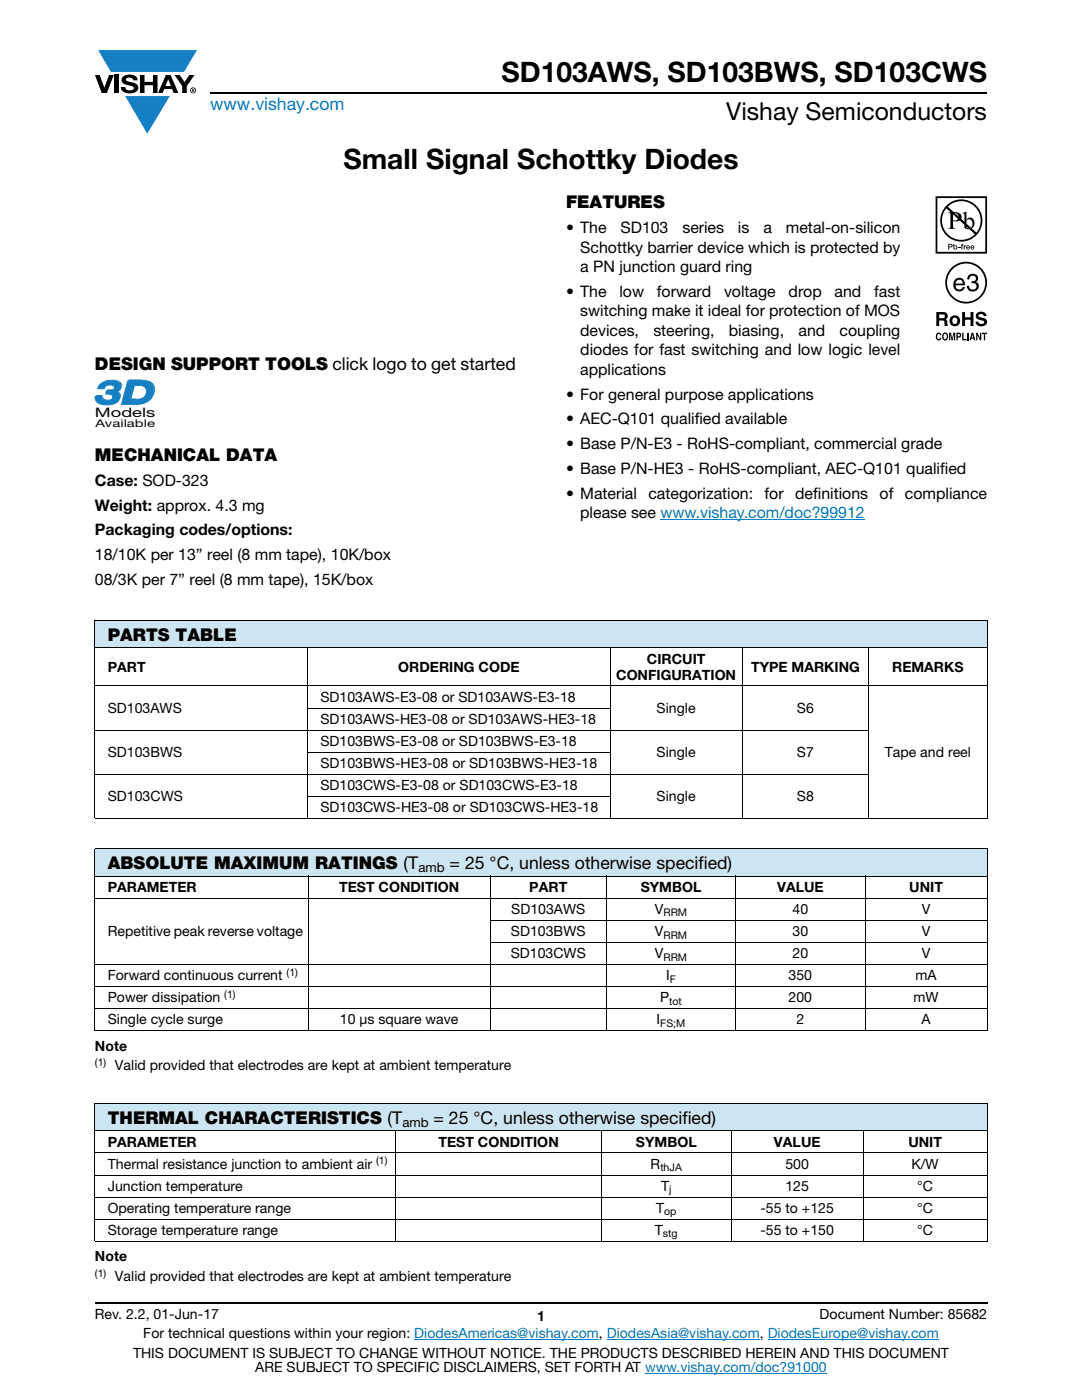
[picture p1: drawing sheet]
<svg xmlns="http://www.w3.org/2000/svg" width="216mm" height="279mm" viewBox="0 0 216 279" stroke-linecap="round" stroke-linejoin="round" font-family="sans-serif">
<defs><g id="words">
<g font-size="5.6">
<text x="100.1" y="16.4">SD103AWS, SD103BWS, SD103CWS</text>
<text x="68.5" y="33.8">Small Signal Schottky Diodes</text>
</g>
<text font-size="4.9" x="144.9" y="24">Vishay Semiconductors</text>
<text font-size="3.5" fill="#007ec4" x="42" y="21.9">www.vishay.com</text>
<g font-size="3.5">
<text x="112.9" y="41.5">FEATURES</text>
<text x="18.9" y="73.8">DESIGN SUPPORT TOOLS click logo to get started</text>
<text x="18.9" y="91.9">MECHANICAL DATA</text>
<text x="21.5" y="127.9">PARTS TABLE</text>
<text x="21.5" y="173.5">ABSOLUTE MAXIMUM RATINGS (T</text>
<text x="89.7" y="173.5">= 25 °C, unless otherwise specified)</text>
<text x="21.5" y="224.3">THERMAL CHARACTERISTICS (T</text>
<text x="86.5" y="224.3">= 25 °C, unless otherwise specified)</text>
</g>
<g font-size="3.2">
<text x="112.9" y="46.6">• The</text>
<text x="123.8" y="46.6">SD103</text>
<text x="136.2" y="46.6">series</text>
<text x="147.3" y="46.6">is</text>
<text x="152.3" y="46.6">a</text>
<text x="156.8" y="46.6">metal-on-silicon</text>
<text x="115.8" y="50.5">Schottky barrier device which is protected by</text>
<text x="112.9" y="59.3">• The</text>
<text x="115.8" y="54.3">a PN junction guard ring</text>
<text x="123.6" y="59.3">low</text>
<text x="131.1" y="59.3">forward</text>
<text x="144.5" y="59.3">voltage</text>
<text x="157.4" y="59.3">drop</text>
<text x="166.5" y="59.3">and</text>
<text x="174.4" y="59.3">fast</text>
<text x="115.8" y="63.2">switching make it ideal for protection of MOS</text>
<text x="115.8" y="67">devices,</text>
<text x="115.8" y="70.9">diodes for fast switching and low logic level</text>
<text x="130.4" y="67">steering,</text>
<text x="145.4" y="67">biasing,</text>
<text x="159.3" y="67">and</text>
<text x="167.5" y="67">coupling</text>
<text x="115.8" y="74.8">applications</text>
<text x="112.9" y="79.7">• For general purpose applications</text>
<text x="112.9" y="84.7">• AEC-Q101 qualified available</text>
<text x="112.9" y="89.6">• Base P/N-E3 - RoHS-compliant, commercial grade</text>
<text x="112.9" y="94.6">• Base P/N-HE3 - RoHS-compliant, AEC-Q101 qualified</text>
<text x="18.9" y="97">Case: SOD-323</text>
<text x="18.9" y="101.9">Weight: approx. 4.3 mg</text>
<text x="112.9" y="99.5">• Material</text>
<text x="129.4" y="99.5">categorization:</text>
<text x="152.6" y="99.5">for</text>
<text x="158.7" y="99.5">definitions</text>
<text x="175.5" y="99.5">of</text>
<text x="180.6" y="99.5">compliance</text>
<text x="18.9" y="106.9">Packaging codes/options:</text>
<text x="115.8" y="103.4">please see www.vishay.com/doc?99912</text>
<text x="18.9" y="111.8">18/10K per 13” reel (8 mm tape), 10K/box</text>
<text x="18.9" y="116.8">08/3K per 7” reel (8 mm tape), 15K/box</text>
</g>
<g font-size="2.8">
<text x="21.5" y="134">PART</text>
<text x="79.5" y="134">ORDERING CODE</text>
<text x="123" y="135.6">CONFIGURATION</text>
<text x="129.1" y="132.4">CIRCUIT</text>
<text x="149.9" y="134">TYPE MARKING</text>
<text x="178" y="134">REMARKS</text>
<text x="21.5" y="142.2">SD103AWS</text>
<text x="63.9" y="140">SD103AWS-E3-08 or SD103AWS-E3-18</text>
<text x="131" y="142.2">Single</text>
<text x="159" y="142.2">S6</text>
<text x="63.9" y="144.4">SD103AWS-HE3-08 or SD103AWS-HE3-18</text>
<text x="63.9" y="148.8">SD103BWS-E3-08 or SD103BWS-E3-18</text>
<text x="21.5" y="151">SD103BWS</text>
<text x="63.9" y="153.2">SD103BWS-HE3-08 or SD103BWS-HE3-18</text>
<text x="131" y="151">Single</text>
<text x="159" y="151">S7</text>
<text x="176.5" y="151">Tape and reel</text>
<text x="21.5" y="159.9">SD103CWS</text>
<text x="63.9" y="157.6">SD103CWS-E3-08 or SD103CWS-E3-18</text>
<text x="131" y="159.9">Single</text>
<text x="159" y="159.9">S8</text>
<text x="63.9" y="162.1">SD103CWS-HE3-08 or SD103CWS-HE3-18</text>
<text x="21.5" y="178">PARAMETER</text>
<text x="67.7" y="178">TEST CONDITION</text>
<text x="105.6" y="178">PART</text>
<text x="127.8" y="178">SYMBOL</text>
<text x="155.1" y="178">VALUE</text>
<text x="181.4" y="178">UNIT</text>
<text x="102" y="182.4">SD103AWS</text>
<text x="130.7" y="182.4">V</text>
<text x="158.1" y="182.4">40</text>
<text x="183.9" y="182.4">V</text>
<text x="21.5" y="186.8">Repetitive peak reverse voltage</text>
<text x="101.9" y="191.2">SD103CWS</text>
<text x="102" y="186.8">SD103BWS</text>
<text x="130.7" y="186.8">V</text>
<text x="130.7" y="191.2">V</text>
<text x="158.1" y="186.8">30</text>
<text x="158.1" y="191.2">20</text>
<text x="183.9" y="186.8">V</text>
<text x="183.9" y="191.2">V</text>
<text x="21.5" y="195.6">Forward continuous current</text>
<text x="132.9" y="195.6">I</text>
<text x="157.4" y="195.6">350</text>
<text x="182.7" y="195.6">mA</text>
<text x="21.5" y="200">Power dissipation</text>
<text x="131.7" y="200">P</text>
<text x="157.4" y="200">200</text>
<text x="182.3" y="200">mW</text>
<text x="18.9" y="209.7">Note</text>
<text x="21.5" y="204.4">Single cycle surge</text>
<text x="67.8" y="204.4">10 μs square wave</text>
<text x="131" y="204.4">I</text>
<text x="158.9" y="204.4">2</text>
<text x="183.9" y="204.4">A</text>
<text x="22.9" y="213.6">Valid provided that electrodes are kept at ambient temperature</text>
<text x="21.5" y="228.8">PARAMETER</text>
<text x="21.5" y="233.2">Thermal resistance junction to ambient air</text>
<text x="87.5" y="228.8">TEST CONDITION</text>
<text x="126.9" y="228.8">SYMBOL</text>
<text x="129.8" y="233.2">R</text>
<text x="154.4" y="228.8">VALUE</text>
<text x="156.7" y="233.2">500</text>
<text x="181.3" y="228.8">UNIT</text>
<text x="181.9" y="233.2">K/W</text>
<text x="21.5" y="237.6">Junction temperature</text>
<text x="131.9" y="237.6">T</text>
<text x="156.7" y="237.6">125</text>
<text x="183" y="237.6">°C</text>
<text x="21.5" y="242">Operating temperature range</text>
<text x="130.9" y="242">T</text>
<text x="151.7" y="242">-55 to +125</text>
<text x="183" y="242">°C</text>
<text x="18.9" y="251.7">Note</text>
<text x="21.5" y="246.4">Storage temperature range</text>
<text x="130.7" y="246.4">T</text>
<text x="151.7" y="246.4">-55 to +150</text>
<text x="183" y="246.4">°C</text>
<text x="22.9" y="255.6">Valid provided that electrodes are kept at ambient temperature</text>
<text x="18.9" y="263.3">Rev. 2.2, 01-Jun-17</text>
<text x="107.2" y="263.6">1</text>
<text x="163.6" y="263.3">Document Number: 85682</text>
<text x="28.6" y="267.1">For technical questions within your region: DiodesAmericas@vishay.com, DiodesAsia@vishay.com, DiodesEurope@vishay.com</text>
<text x="26.5" y="271">THIS DOCUMENT IS SUBJECT TO CHANGE WITHOUT NOTICE. THE PRODUCTS DESCRIBED HEREIN AND THIS DOCUMENT</text>
<text x="50.9" y="273.8">ARE SUBJECT TO SPECIFIC DISCLAIMERS, SET FORTH AT www.vishay.com/doc?91000</text>
</g>
<text font-size="2.6" fill="#050504" x="18.9" y="83.2">Models</text>
<g font-size="2.6">
<text x="83.5" y="174.1">amb</text>
<text x="80.3" y="224.9">amb</text>
</g>
<text font-size="2.1" fill="#050504" x="19" y="85.2">Available</text>
<g font-size="2.1">
<text x="132.4" y="182.9">RRM</text>
<text x="132.4" y="187.3">RRM</text>
<text x="132.4" y="191.7">RRM</text>
<text x="57.2" y="194.8">(1)</text>
<text x="133.6" y="196.1">F</text>
<text x="44.7" y="199.2">(1)</text>
<text x="133.5" y="200.5">tot</text>
<text x="131.7" y="204.9">FS;M</text>
<text x="18.9" y="212.7">(1)</text>
<text x="75.1" y="232.4">(1)</text>
<text x="131.8" y="233.7">thJA</text>
<text x="133.5" y="238.1">j</text>
<text x="132.5" y="242.5">op</text>
<text x="132.3" y="247">stg</text>
<text x="18.9" y="254.8">(1)</text>
</g>
</g></defs>
<g fill="#147fc3">
<path d="M19.6 10h19.7l-2.6 4.3h-1.1h-13.5z"/>
<path d="M25 19.2h8.9l-4.5 7.5z"/>
</g>
<g fill="#000">
<path d="M18.9 15h1l.9 2.5 1-2.5h.9l-1.4 3.6h-1zM22.9 15h.9v3.6h-.9zM24.6 15.3a2.1 2.1 0 0 1 2.8 .3l.1 .4h-.9a.79 .79 0 0 0-.7-.5 .79 .79 0 0 0-.8 .4l.3 .3 1 .2a1.08 1.08 0 0 1 1.2 1 1.08 1.08 0 0 1-1.1 1.2 1.73 1.73 0 0 1-2.4-1.2h.9a.96 .96 0 0 0 .8 .6 .96 .96 0 0 0 .9-.4 1.31 1.31 0 0 0-1.2-.6 1.03 1.03 0 0 1-1.1-.6 1.03 1.03 0 0 1 .2-1.1zM27.9 15h.9v1.3h1.7v-1.3h.9v3.6h-.9v-1.6h-1.7v1.6h-.9zM34.8 15h1.1l.9 1.4 1-1.4h1l-1.5 2.2v1.4h-.9v-1.4z"/>
<path d="M33.6 15.9l.5 1.3h-1.1zM33.1 15l-1.6 3.6h1l.3-.8h1.5l.3 .8h1l-1.6-3.6z"/>
<path d="M38.4 17.8h.2v.2h-.2zM38.3 17.7v.7h.1v-.3l.4 .3-.2-.3 .2-.2-.1-.2z"/>
<path d="M38.1 18a.46 .46 0 0 1 .9 0 .46 .46 0 0 1-.9 0zM37.9 18a.6 .6 0 0 0 1.2 0 .6 .6 0 0 0-1.2 0z"/>
</g>
<path d="M42 18.6h155M18.9 260h178.1" fill="none" stroke="#000" stroke-width=".36"/>
<path d="M131.8 103.6h40.8M82.7 267.3h36.8M121.1 267.3h30.5M128.7 274h36.3M153.2 267.3h34.1" fill="none" stroke="#007ec4" stroke-width=".2"/>
<g fill="#fff">
<path d="M43.1 41.8h36v23.9h-36z"/>
<path d="M18.9 75.7h12.1v10h-12.1z"/>
</g>
<path d="M19.3 78.8h1.2l-.3 .3h-1.2z" fill="#0d567f"/>
<path d="M20.5 78.8l-.3 .4z" fill="#09537d"/>
<path d="M20.5 78.9l-.3 .4z" fill="#0d5781"/>
<path d="M20.5 79l-.3 .3z" fill="#105a84"/>
<path d="M20.5 79l-.3 .4z" fill="#115c88"/>
<path d="M20.5 79.1l-.3 .4z" fill="#145f8c"/>
<path d="M20.5 79.2l-.2 .3z" fill="#146190"/>
<path d="M20.6 79.2l-.3 .4z" fill="#156494"/>
<path d="M20.6 79.3l.2 .2-.3 .3-.2-.2z" fill="#176797"/>
<path d="M20.8 79.5l.1 .1-.3 .3-.1-.1z" fill="#156494"/>
<path d="M20.9 79.6h.1l-.4 .3z" fill="#146190"/>
<path d="M21 79.6l.1 .1-.4 .2z" fill="#145f8c"/>
<path d="M21.1 79.7h.1l-.4 .3z" fill="#115c88"/>
<path d="M21.2 79.7h.1l-.4 .3z" fill="#105a84"/>
<path d="M21.3 79.7h.2l-.5 .3z" fill="#0d5781"/>
<path d="M21.5 79.7h.2l-.4 .3h-.1z" fill="#09537d"/>
<path d="M21.7 79.7h.1l-.5 .3z" fill="#0e5078"/>
<path d="M21.8 79.7h.2l-.5 .3z" fill="#0e4e73"/>
<path d="M22 79.7h.2l-.5 .3z" fill="#0a496f"/>
<path d="M22.2 79.7l.1-.1-.4 .4z" fill="#09486a"/>
<path d="M22.3 79.6l.3-.2-.6 .5z" fill="#034466"/>
<path d="M21.6 77.7h.4l-.4 .3h-.3z" fill="#0d567f"/>
<path d="M21.3 76.8l-.4 .5z" fill="#034466"/>
<path d="M21.2 77l-.4 .4z" fill="#09486a"/>
<path d="M21.1 77.1l-.3 .4z" fill="#0a496f"/>
<path d="M21.1 77.2l-.3 .4z" fill="#0e4e73"/>
<path d="M22 77.7h.1l-.5 .3z" fill="#09537d"/>
<path d="M22.1 77.7h.2l-.3 .3h-.2z" fill="#0e5078"/>
<path d="M22.3 77.7l.2-.1-.5 .4z" fill="#0e4e73"/>
<path d="M22.5 77.6h.2l-.5 .3z" fill="#0a496f"/>
<path d="M22.7 77.6l.1-.1-.4 .4z" fill="#09486a"/>
<path d="M22.8 77.5l.2-.1-.5 .4z" fill="#034466"/>
<path d="M23.2 78h.2l-.3 .3h-.2z" fill="#115c88"/>
<path d="M23.4 78l.1 .1-.3 .3-.1-.1z" fill="#145f8c"/>
<path d="M23.5 78.1l.2 .1-.3 .3-.2-.1z" fill="#146190"/>
<path d="M23.7 78.1l.1 .1-.3 .4-.1-.1z" fill="#156494"/>
<path d="M23.8 78.2l.2 .3-.3 .3-.2-.3z" fill="#176797"/>
<path d="M24 78.5l.1 .1-.3 .3-.1-.1z" fill="#156494"/>
<path d="M24.1 78.6l-.3 .4z" fill="#146190"/>
<path d="M24.1 78.7l-.3 .4z" fill="#145f8c"/>
<path d="M24.1 78.8l-.3 .4z" fill="#115c88"/>
<path d="M24.2 78.9l-.3 .4z" fill="#105a84"/>
<path d="M24.2 79l-.3 .4z" fill="#0d5781"/>
<path d="M24.2 79.1l-.4 .4z" fill="#09537d"/>
<path d="M24.1 79.2l-.3 .4z" fill="#0e5078"/>
<path d="M24.1 79.3l-.3 .4z" fill="#0e4e73"/>
<path d="M24.1 79.4l-.4 .4z" fill="#0a496f"/>
<path d="M24.1 79.5l-.4 .4z" fill="#09486a"/>
<g fill="#034466">
<path d="M24 79.6l-.5 .5z"/>
<path d="M20.3 76.4l.5-.4-.8 .7z"/>
</g>
<path d="M20.8 76l.3-.1-.6 .4z" fill="#09486a"/>
<path d="M21.1 75.9l.3-.1-.6 .4z" fill="#0a496f"/>
<path d="M21.4 75.8h.4l-.3 .3h-.4z" fill="#0e4e73"/>
<path d="M21.8 75.8l.3-.1-.3 .4h-.3z" fill="#0e5078"/>
<path d="M22.1 75.7h.2l-.5 .4z" fill="#09537d"/>
<path d="M19.9 76.8a3.2 3.2 0 0 1 4.1 0 1.07 1.07 0 0 1-1.1 1.5 1.09 1.09 0 0 1 1 1 1.09 1.09 0 0 1-.8 1.1 4.2 4.2 0 0 1-3.6 0l-.5-.8v-.5h1.2a1 1 0 0 0 1.5 .9 .7 .7 0 0 0 .8-.7 .7 .7 0 0 0-.9-.7h-.5l.2-.6h.4a.81 .81 0 0 0 1.1-.9 1.28 1.28 0 0 0-2 .5h-1.3z" fill="#177fc3"/>
<path d="M19.9 76.8a3.2 3.2 0 0 1 4.1 0 1.07 1.07 0 0 1-1.1 1.5 1.09 1.09 0 0 1 1 1 1.09 1.09 0 0 1-.8 1.1 4.2 4.2 0 0 1-3.6 0l-.5-.8v-.5h1.2a1 1 0 0 0 1.5 .9 .7 .7 0 0 0 .8-.7 .7 .7 0 0 0-.9-.7h-.5l.2-.6h.4a.81 .81 0 0 0 1.1-.9 1.28 1.28 0 0 0-2 .5h-1.3z" fill="none" stroke="#177fc3" stroke-width=".2"/>
<path d="M22.3 75.7h.2l-.3 .4h-.2z" fill="#09537d"/>
<path d="M22.5 75.7l.4 .1-.3 .3h-.4z" fill="#0d5781"/>
<path d="M22.9 75.8h.3l-.3 .3h-.3z" fill="#105a84"/>
<path d="M23.2 75.8l.2 .1-.3 .3-.2-.1z" fill="#115c88"/>
<path d="M23.4 75.9l.2 .1-.3 .3-.2-.1z" fill="#145f8c"/>
<path d="M23.6 76l.2 .1-.3 .3-.2-.1z" fill="#146190"/>
<path d="M23.8 76.1l.2 .1-.3 .3-.2-.1z" fill="#156494"/>
<path d="M24 76.2l.3 .3-.3 .3-.3-.3z" fill="#176797"/>
<path d="M24.3 76.5v.1l-.3 .3v-.1z" fill="#156494"/>
<path d="M24.3 76.6l-.2 .4z" fill="#146190"/>
<path d="M24.4 76.7l-.3 .4z" fill="#145f8c"/>
<path d="M24.4 76.8l-.3 .4z" fill="#115c88"/>
<path d="M24.4 76.9l-.3 .4z" fill="#105a84"/>
<path d="M24.4 77l-.3 .3z" fill="#0d5781"/>
<path d="M24.4 77l-.3 .4z" fill="#09537d"/>
<path d="M24.4 77.1l-.3 .4z" fill="#0e5078"/>
<path d="M24.4 77.1l-.3 .4z" fill="#0e4e73"/>
<path d="M24.4 77.2l-.4 .4z" fill="#0a496f"/>
<path d="M24.3 77.3l-.3 .4z" fill="#09486a"/>
<path d="M24.3 77.4l-.5 .5z" fill="#034466"/>
<path d="M26.2 79.5h1.1l-.3 .4h-1.1z" fill="#0d567f"/>
<path d="M27.3 79.5h.1l-.4 .4z" fill="#09537d"/>
<path d="M27.4 79.5h.3l-.3 .3-.3 .1z" fill="#0e5078"/>
<path d="M27.7 79.5h.3l-.3 .3h-.3z" fill="#0e4e73"/>
<path d="M28 79.5l.2-.1-.5 .4z" fill="#0a496f"/>
<path d="M28.2 79.4l.3-.1-.6 .4z" fill="#09486a"/>
<path d="M28.5 79.3l.6-.4-.9 .7z" fill="#034466"/>
<path d="M27 76.6l-.8 2.9-.3 .4 .8-3z" fill="#074f76"/>
<path d="M25.5 75.9h2.6" fill="none" stroke="#0d567f" stroke-width=".31"/>
<path d="M28.1 75.7h.4l-.3 .4h-.4z" fill="#09537d"/>
<path d="M28.5 75.8h.4l-.3 .3h-.4z" fill="#0d5781"/>
<path d="M28.9 75.8h.4l-.3 .4-.4-.1z" fill="#105a84"/>
<path d="M29.3 75.8l.3 .1-.3 .3h-.3z" fill="#115c88"/>
<path d="M29.6 75.9l.2 .1-.3 .3-.2-.1z" fill="#145f8c"/>
<path d="M29.8 76l.3 .1-.3 .3-.3-.1z" fill="#146190"/>
<path d="M30.1 76.1l.2 .2-.3 .3-.2-.2z" fill="#156494"/>
<path d="M30.3 76.3l.5 .5-.4 .3-.4-.5z" fill="#176797"/>
<path d="M30.8 76.8l.1 .2-.4 .3-.1-.2z" fill="#156494"/>
<path d="M30.9 77v.1l-.3 .3-.1-.1z" fill="#146190"/>
<path d="M30.9 77.1v.2l-.3 .3v-.2z" fill="#145f8c"/>
<path d="M30.9 77.3l-.2 .4z" fill="#115c88"/>
<path d="M31 77.4l-.3 .5z" fill="#105a84"/>
<path d="M31 77.6v.2l-.3 .4v-.3z" fill="#0d5781"/>
<path d="M31 77.8l-.4 .6z" fill="#09537d"/>
<path d="M30.9 78.1l-.3 .5z" fill="#0e5078"/>
<path d="M30.9 78.3l-.4 .5z" fill="#0e4e73"/>
<path d="M30.8 78.5l-.4 .5z" fill="#0a496f"/>
<path d="M30.7 78.7l-.4 .6z" fill="#09486a"/>
<path d="M30.6 79l-.6 .7z" fill="#034466"/>
<path d="M26.7 76.9l-.8 3a3.2 3.2 0 0 0 3.1-.9 1.27 1.27 0 0 0 .1-1.5 1.27 1.27 0 0 0-1.3-.6zM25.5 76.1a8.4 8.4 0 0 1 4.2 .3 2.15 2.15 0 0 1 1 2.1 2.15 2.15 0 0 1-1.4 1.7 9.3 9.3 0 0 1-5.1 .5z" fill="#177fc3"/>
<path d="M25.5 76.1a8.4 8.4 0 0 1 4.2 .3 2.15 2.15 0 0 1 1 2.1 2.15 2.15 0 0 1-1.4 1.7 9.3 9.3 0 0 1-5.1 .5zM26.7 76.9a2.55 2.55 0 0 1 2.3 .5 1.76 1.76 0 0 1-.2 1.8 1.76 1.76 0 0 1-1.8 .7h-1.1z" fill="none" stroke="#177fc3" stroke-width=".2"/>
<path d="M186.7 39.2h10.3v28.8h-10.3z" fill="#fff"/>
<g fill="#000">
<path d="M191.2 49.3h.4v.1h-.4zM191.9 48.7h.3l-.2 .2 .2 .1v.1h-.2v.7h-.1v-.7h-.2zM192.3 49h.2v.1l.3-.1v.1l-.3 .1v.6h-.2zM193.3 54.9a1.07 1.07 0 0 1 1.3-.2 1.07 1.07 0 0 1 .5 1.2l-.4 .4a1.06 1.06 0 0 1 .5 1.4 1.06 1.06 0 0 1-1.4 .5l-.2-.1a1.02 1.02 0 0 1-.7-1.1h.5a.71 .71 0 0 0 .9 .8 .71 .71 0 0 0 .3-1.2l-.7-.1v-.4a.59 .59 0 0 0 .8-.4 .59 .59 0 0 0-.6-.7 .66 .66 0 0 0-.7 .8h-.4zM186.9 66.6l.4-.2h.3l.2 .5-.6-.2a.66 .66 0 0 0 .1 1l.3-.3h.2a.54 .54 0 0 1-.4 .6 .54 .54 0 0 1-.6-.5zM189.4 66.4h.4l.2 1.2 .2-1.2h.4v1.5h-.3v-1.3l-.2 1.3h-.2l-.3-1.3v1.3h-.2zM192 66.4h.3v1.2h.6v.3h-.9zM192 62.3h.6v1h1.1v-1h.5v2.8h-.5v-1.3h-1.1v1.3h-.6zM193 66.4h.3v1.5h-.3zM195 62.4a1.15 1.15 0 0 1 1.9 .7h-.6v-.2a.68 .68 0 0 0-1-.1v.4l.2 .1a1.29 1.29 0 0 1 1.5 .9 1.17 1.17 0 0 1-1.2 .9 1.17 1.17 0 0 1-1.1-.9h.5l.1 .2a.67 .67 0 0 0 1.1-.1l-.3-.3-.5-.1a.82 .82 0 0 1-.9-.5 .82 .82 0 0 1 .3-1zM194.8 66.4h.3l.5 1.1v-1.1h.2v1.5h-.3l-.5-1.1v1.1h-.2zM195.9 66.4h1.1v.3h-.4v1.2h-.3v-1.2h-.4z"/>
<path d="M187 39.5h9.6v10.8h-9.6zM186.7 39.2v11.4h10.3v-11.4z"/>
<path d="M189 56.4a3.8 3.8 0 0 1 7.6 0 3.8 3.8 0 0 1-7.6 0zM188.6 56.4a4.2 4.2 0 0 0 8.4 0 4.2 4.2 0 0 0-8.4 0z"/>
<path d="M189.1 41.3a3.9 3.9 0 0 1 5.3-.2 3.9 3.9 0 0 1 .4 5.3zM188.8 41.6l5.7 5.2a3.9 3.9 0 0 1-5.3 .1 3.9 3.9 0 0 1-.4-5.3zM187.6 44a4.2 4.2 0 0 0 8.4 0 4.2 4.2 0 0 0-8.4 0z"/>
<path d="M189.4 48.8v.4h.4v-.3zM189.2 48.7h.7l.2 .3-.2 .3-.5 .1v.4h-.2z"/>
<path d="M190.2 42.6v1.3a.75 .75 0 0 0 1.1-.6 .75 .75 0 0 0-1.1-.7zM189.2 42.4a2.81 2.81 0 0 1 2.4 .3 .97 .97 0 0 1 0 1.2 .97 .97 0 0 1-1.2 .2h-.2v1.1v.2l.5 .3h-1.5l.3-.2 .1-.3v-2.3v-.3z"/>
<path d="M190.4 49.4a.26 .26 0 0 0 .5 0 .26 .26 0 0 0-.5 0zM190.2 48.7h.2v.4a.38 .38 0 0 1 .5 0 .38 .38 0 0 1 0 .6 .38 .38 0 0 1-.5 0l-.2 .1z"/>
<path d="M190.9 56.1l-.2 .5h1.4a.7 .7 0 0 0-.4-.7 .7 .7 0 0 0-.8 .2zM190.7 55.7a1.18 1.18 0 0 1 1.4-.1 1.18 1.18 0 0 1 .5 1.3h-1.9a.73 .73 0 0 0 .5 .9 .73 .73 0 0 0 .9-.5h.4a1.21 1.21 0 0 1-1.6 .8 1.21 1.21 0 0 1-.6-1.7z"/>
<path d="M192.8 44v1.3l.2 .2a.72 .72 0 0 0 .8-.1 .72 .72 0 0 0 .3-.7 .72 .72 0 0 0-.4-.8 .72 .72 0 0 0-.9 .1zM192.1 42.5l.7-.3v1.6a.89 .89 0 0 1 1.1-.3 .89 .89 0 0 1 .6 1 1.23 1.23 0 0 1-.7 1.2 1.23 1.23 0 0 1-1.4-.2v-2.7z"/>
<path d="M193 49.2v.1h.4l-.2-.2zM193 49h.4l.2 .4h-.6v.2l.5-.1a.42 .42 0 0 1-.6 .2 .42 .42 0 0 1 .1-.7z"/>
<path d="M193.9 49.2l-.1 .1h.5l-.3-.2zM193.8 49h.5l.1 .4h-.6l.1 .2 .5-.1a.42 .42 0 0 1-.6 .2 .42 .42 0 0 1 0-.7z"/>
<path d="M187.4 62.8v.7h.9a.39 .39 0 0 0 .1-.7zM186.8 62.3h1.4a.79 .79 0 0 1 .8 .4 .79 .79 0 0 1-.1 .9l-.2 .1a.98 .98 0 0 1 .4 1.2l.1 .2h-.7l-.2-1.1h-.9v1.1h-.6z"/>
<path d="M188.4 66.7a.64 .64 0 0 0 .2 1l.1-.1a.64 .64 0 0 0-.1-1zM188.2 66.5l.2-.1a.56 .56 0 0 1 .7 .3 .82 .82 0 0 1-.5 1.3l-.2-.1a.89 .89 0 0 1-.2-1.4z"/>
<path d="M190.3 63.5a.63 .63 0 0 0-.3 .7 .63 .63 0 0 0 .8 .4 .63 .63 0 0 0 .2-.8 .63 .63 0 0 0-.7-.3zM189.5 64a1.09 1.09 0 0 1 2.1 0 1.09 1.09 0 0 1-2.1 0z"/>
<path d="M191.1 66.7v.4l.4-.1v-.3zM190.8 66.4h.6a.5 .5 0 0 1 .4 .5 .5 .5 0 0 1-.4 .5h-.3v.5h-.3z"/>
<path d="M194 66.7l-.1 .6h.3zM193.9 66.4h.3l.4 1.5h-.3v-.3h-.5l-.1 .3h-.3z"/>
</g>
<g fill="#cce5f3">
<path d="M18.9 123.8h178.1v5.5h-178.1z"/>
<path d="M18.9 169.4h178.1v5.5h-178.1z"/>
<path d="M18.9 220.2h178.1v5.5h-178.1z"/>
</g>
<g fill="none" stroke="#000" stroke-width=".2">
<path d="M18.9 123.8h178.1M18.9 129.3h178.1M18.9 136.9h178.1M18.9 123.9v39.4M61.4 129.2v34.2M121.8 129.2v34.2M148.1 129.2v34.2M173.4 129.2v34.2M197 123.9v39.4M18.9 145.7h154.5M18.9 154.5h154.5M61.3 141.3h60.6"/>
<path d="M61.3 150.1h60.6M61.3 158.9h60.6M18.9 163.4h178.1M18.9 169.4h178.1M18.9 174.9h178.1M18.9 179.3h178.1M18.9 169.4v36.2M61.5 174.8v31M97.8 174.8v31M121 174.8v31M146.8 174.8v31M172.6 174.8v31"/>
<path d="M197 169.4v36.2M18.9 192.5h178.1M18.9 196.9h178.1M97.7 183.7h99.3M97.7 188.1h99.3M18.9 201.3h178.1M18.9 205.7h178.1M18.9 220.2h178.1M18.9 225.7h178.1M18.9 230.1h178.1M18.9 234.5h178.1M18.9 238.9h178.1"/>
<path d="M18.9 220.3v27.3M79 225.6v22.2M120 225.6v22.2M145.9 225.6v22.2M172.2 225.6v22.2M197 220.3v27.3M18.9 243.3h178.1M18.9 247.7h178.1"/>
</g>
<use href="#words"/>
</svg>
